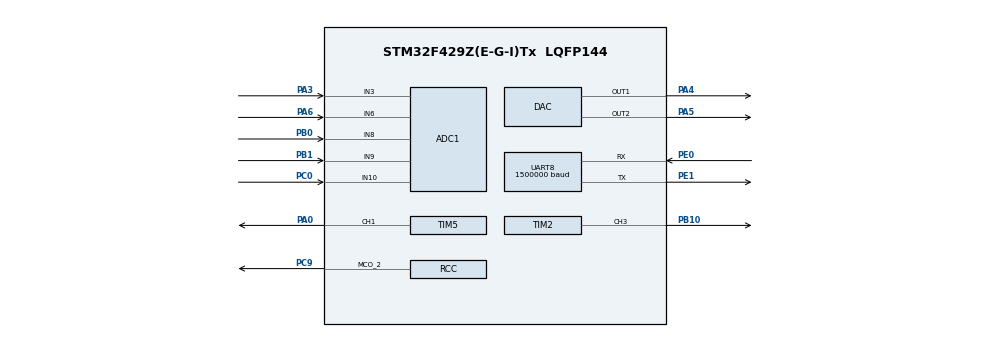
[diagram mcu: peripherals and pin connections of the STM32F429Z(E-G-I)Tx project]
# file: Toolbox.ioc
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ADC1.Channel=ADC_CHANNEL_VREFINT
ADC1.Channel-16\#ChannelRegularConversion=ADC_CHANNEL_TEMPSENSOR
ADC1.Channel-17\#ChannelRegularConversion=ADC_CHANNEL_VREFINT
ADC1.Channel-18\#ChannelRegularConversion=ADC_CHANNEL_VBAT
ADC1.DMAContinuousRequests=ENABLE
ADC1.EOCSelection=EOC_SEQ_CONV
ADC1.ExternalTrigConv=ADC_EXTERNALTRIGCONV_T5_CC1
ADC1.ExternalTrigConvEdge=ADC_EXTERNALTRIGCONVEDGE_RISING
ADC1.NbrOfConversion=3
ADC1.Rank-17\#ChannelRegularConversion=2
ADC1.Rank-18\#ChannelRegularConversion=3
ADC1.SamplingTime-18\#ChannelRegularConversion=ADC_SAMPLETIME_3CYCLES
ADC1.ScanConvMode=ENABLE
ADC1.master=1
Dma.ADC1.2.Channel=DMA_CHANNEL_0
Dma.ADC1.2.Direction=DMA_PERIPH_TO_MEMORY
Dma.ADC1.2.FIFOMode=DMA_FIFOMODE_DISABLE
Dma.ADC1.2.FIFOThreshold=DMA_FIFO_THRESHOLD_HALFFULL
Dma.ADC1.2.Instance=DMA2_Stream0
Dma.ADC1.2.MemBurst=DMA_MBURST_SINGLE
Dma.ADC1.2.MemDataAlignment=DMA_MDATAALIGN_HALFWORD
Dma.ADC1.2.MemInc=DMA_MINC_ENABLE
Dma.ADC1.2.Mode=DMA_CIRCULAR
Dma.ADC1.2.PeriphBurst=DMA_PBURST_SINGLE
Dma.ADC1.2.PeriphDataAlignment=DMA_PDATAALIGN_HALFWORD
Dma.ADC1.2.PeriphInc=DMA_PINC_DISABLE
Dma.ADC1.2.Priority=DMA_PRIORITY_HIGH
Dma.Request0=UART8_TX
Dma.Request1=UART8_RX
Dma.Request2=ADC1
Dma.UART8_RX.1.Channel=DMA_CHANNEL_5
Dma.UART8_RX.1.Direction=DMA_PERIPH_TO_MEMORY
Dma.UART8_RX.1.FIFOMode=DMA_FIFOMODE_DISABLE
Dma.UART8_RX.1.FIFOThreshold=DMA_FIFO_THRESHOLD_HALFFULL
Dma.UART8_RX.1.Instance=DMA1_Stream6
Dma.UART8_RX.1.MemBurst=DMA_MBURST_SINGLE
Dma.UART8_RX.1.MemDataAlignment=DMA_MDATAALIGN_BYTE
Dma.UART8_RX.1.MemInc=DMA_MINC_ENABLE
Dma.UART8_RX.1.Mode=DMA_CIRCULAR
Dma.UART8_RX.1.PeriphBurst=DMA_PBURST_SINGLE
Dma.UART8_RX.1.PeriphDataAlignment=DMA_PDATAALIGN_BYTE
Dma.UART8_RX.1.PeriphInc=DMA_PINC_DISABLE
Dma.UART8_RX.1.Priority=DMA_PRIORITY_VERY_HIGH
Dma.UART8_TX.0.Channel=DMA_CHANNEL_5
Dma.UART8_TX.0.Direction=DMA_MEMORY_TO_PERIPH
Dma.UART8_TX.0.FIFOMode=DMA_FIFOMODE_ENABLE
Dma.UART8_TX.0.FIFOThreshold=DMA_FIFO_THRESHOLD_1QUARTERFULL
Dma.UART8_TX.0.Instance=DMA1_Stream0
Dma.UART8_TX.0.MemBurst=DMA_MBURST_SINGLE
Dma.UART8_TX.0.MemDataAlignment=DMA_MDATAALIGN_BYTE
Dma.UART8_TX.0.MemInc=DMA_MINC_ENABLE
Dma.UART8_TX.0.Mode=DMA_NORMAL
Dma.UART8_TX.0.PeriphBurst=DMA_PBURST_SINGLE
Dma.UART8_TX.0.PeriphDataAlignment=DMA_PDATAALIGN_BYTE
Dma.UART8_TX.0.PeriphInc=DMA_PINC_DISABLE
Dma.UART8_TX.0.Priority=DMA_PRIORITY_VERY_HIGH
Mcu.Family=STM32F4
Mcu.Name=STM32F429Z(E-G-I)Tx
Mcu.Package=LQFP144
NVIC.ADC_IRQn=true\:3\:0\:true
NVIC.DMA1_Stream0_IRQn=true\:1\:0\:true
NVIC.DMA1_Stream6_IRQn=true\:1\:0\:true
NVIC.DMA2_Stream0_IRQn=true\:2\:0\:true
NVIC.PriorityGroup=NVIC_PRIORITYGROUP_4
PA0/WKUP.GPIO_ModeDefaultPP=GPIO_MODE_AF_OD
PA0/WKUP.GPIO_PuPd=GPIO_NOPULL
PA0/WKUP.GPIO_Speed=GPIO_SPEED_LOW
PA0/WKUP.Signal=S_TIM5_CH1
PA1.Signal=ETH_REF_CLK
PA11.Signal=USB_OTG_FS_DM
PA12.Signal=USB_OTG_FS_DP
PA13.Mode=JTAG(5-pin)
PA13.Signal=SYS_JTMS-SWDIO
PA14.Mode=JTAG(5-pin)
PA14.Signal=SYS_JTCK-SWCLK
PA15.Mode=JTAG(5-pin)
PA15.Signal=SYS_JTDI
PA2.Signal=ETH_MDIO
PA3.Signal=ADCx_IN3
PA4.Signal=COMP_DAC1_group
PA5.Signal=COMP_DAC2_group
PA6.Signal=ADCx_IN6
PA7.Signal=ETH_CRS_DV
PA9.Signal=USB_OTG_FS_VBUS
PB0.Signal=ADCx_IN8
PB1.Signal=ADCx_IN9
PB10.GPIO_ModeDefaultPP=GPIO_MODE_AF_PP
PB10.GPIO_PuPd=GPIO_PULLUP
PB10.GPIO_Speed=GPIO_SPEED_HIGH
PB10.Signal=S_TIM2_CH3
PB11.Signal=ETH_TX_EN
PB12.Signal=ETH_TXD0
PB13.Signal=ETH_TXD1
PB3.Mode=JTAG(5-pin)
PB3.Signal=SYS_JTDO-SWO
PB4.Mode=JTAG(5-pin)
PB4.Signal=SYS_JTRST
PC0.Signal=ADCx_IN10
PC1.Signal=ETH_MDC
PC12.Signal=SDIO_CK
PC4.Signal=ETH_RXD0
PC5.Signal=ETH_RXD1
PC8.Signal=SDIO_D0
PC9.GPIO_Mode=GPIO_MODE_AF_PP
PC9.GPIO_PuPd=GPIO_NOPULL
PC9.GPIO_Speed=GPIO_SPEED_HIGH
PC9.Mode=Clock-out-2
PC9.Signal=RCC_MCO_2
PD2.Signal=SDIO_CMD
PE0.GPIO_Mode=GPIO_MODE_AF_PP
PE0.GPIO_PuPd=GPIO_PULLUP
PE0.GPIO_Speed=GPIO_SPEED_HIGH
PE0.Mode=Asynchronous
PE0.Signal=UART8_RX
PE1.GPIO_Mode=GPIO_MODE_AF_PP
PE1.GPIO_PuPd=GPIO_PULLUP
PE1.GPIO_Speed=GPIO_SPEED_HIGH
PE1.Mode=Asynchronous
PE1.Signal=UART8_TX
PH0/OSC_IN.Mode=HSE-External-Oscillator
PH0/OSC_IN.Signal=RCC_OSC_IN
PH1/OSC_OUT.Mode=HSE-External-Oscillator
PH1/OSC_OUT.Signal=RCC_OSC_OUT
ProjectManager.TargetToolchain=TrueSTUDIO 4.3.1
RCC.48MHZClocksFreq_Value=45000000
RCC.AHBFreq_Value=180000000
RCC.APB1CLKDivider=RCC_HCLK_DIV4
RCC.APB1Freq_Value=45000000
RCC.APB1TimFreq_Value=90000000
RCC.APB2CLKDivider=RCC_HCLK_DIV2
RCC.APB2Freq_Value=90000000
RCC.APB2TimFreq_Value=180000000
RCC.CortexFreq_Value=22500000
RCC.HCLKFreq_Value=180000000
RCC.HSE_VALUE=16000000
RCC.HSI_VALUE=16000000
RCC.LSE_VALUE=32768
RCC.PLLI2SN=400
RCC.PLLN=360
RCC.PLLQ=8
RCC.PLLSourceVirtual=RCC_PLLSOURCE_HSE
RCC.RCC_MCO2Source=RCC_MCO2SOURCE_PLLI2SCLK
RCC.RCC_MCODiv2=RCC_MCODIV_4
RCC.SYSCLKFreq_VALUE=180000000
RCC.SYSCLKSource=RCC_SYSCLKSOURCE_PLLCLK
RCC.VCOOutputFreq_Value=360000000
SH.ADCx_IN10.0=ADC1_IN10,IN10
SH.ADCx_IN3.0=ADC1_IN3,IN3
SH.ADCx_IN6.0=ADC1_IN6,IN6
SH.ADCx_IN8.0=ADC1_IN8,IN8
SH.ADCx_IN9.0=ADC1_IN9,IN9
SH.COMP_DAC1_group.0=DAC_OUT1,DAC_OUT1
SH.COMP_DAC2_group.0=DAC_OUT2,DAC_OUT2
SH.S_TIM2_CH3.0=TIM2_CH3,PWM Generation3 CH3
SH.S_TIM5_CH1.0=TIM5_CH1,PWM Generation1 CH1
TIM2.Channel-PWM\ Generation3\ CH3=TIM_CHANNEL_3
TIM2.OCFastMode_PWM-PWM\ Generation3\ CH3=TIM_OCFAST_ENABLE
TIM2.Period=9000
TIM2.Pulse-PWM\ Generation3\ CH3=3000
TIM5.OCFastMode_PWM-PWM\ Generation1\ CH1=TIM_OCFAST_ENABLE
TIM5.Period=180000000
TIM5.Pulse-PWM\ Generation1\ CH1=10
TIM5.TIM_MasterOutputTrigger=TIM_TRGO_OC1REF
UART8.BaudRate=1500000
VP_ADC1_TempSens_Input.Mode=IN-TempSens
VP_ADC1_Vbat_Input.Mode=IN-Vbat
VP_ADC1_Vref_Input.Mode=IN-Vrefint
VP_TIM2_VS_ClockSourceINT.Mode=Internal
VP_TIM5_VS_ClockSourceINT.Mode=Internal

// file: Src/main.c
/**
  ******************************************************************************
  * File Name          : main.c
  * Date               : 05/04/2015 00:15:51
  * Description        : Main program body
  ******************************************************************************
  *
  * COPYRIGHT(c) 2015 STMicroelectronics
  *
  * Redistribution and use in source and binary forms, with or without modification,
  * are permitted provided that the following conditions are met:
  *   1. Redistributions of source code must retain the above copyright notice,
  *      this list of conditions and the following disclaimer.
  *   2. Redistributions in binary form must reproduce the above copyright notice,
  *      this list of conditions and the following disclaimer in the documentation
  *      and/or other materials provided with the distribution.
  *   3. Neither the name of STMicroelectronics nor the names of its contributors
  *      may be used to endorse or promote products derived from this software
  *      without specific prior written permission.
  *
  * THIS SOFTWARE IS PROVIDED BY THE COPYRIGHT HOLDERS AND CONTRIBUTORS "AS IS"
  * AND ANY EXPRESS OR IMPLIED WARRANTIES, INCLUDING, BUT NOT LIMITED TO, THE
  * IMPLIED WARRANTIES OF MERCHANTABILITY AND FITNESS FOR A PARTICULAR PURPOSE ARE
  * DISCLAIMED. IN NO EVENT SHALL THE COPYRIGHT HOLDER OR CONTRIBUTORS BE LIABLE
  * FOR ANY DIRECT, INDIRECT, INCIDENTAL, SPECIAL, EXEMPLARY, OR CONSEQUENTIAL
  * DAMAGES (INCLUDING, BUT NOT LIMITED TO, PROCUREMENT OF SUBSTITUTE GOODS OR
  * SERVICES; LOSS OF USE, DATA, OR PROFITS; OR BUSINESS INTERRUPTION) HOWEVER
  * CAUSED AND ON ANY THEORY OF LIABILITY, WHETHER IN CONTRACT, STRICT LIABILITY,
  * OR TORT (INCLUDING NEGLIGENCE OR OTHERWISE) ARISING IN ANY WAY OUT OF THE USE
  * OF THIS SOFTWARE, EVEN IF ADVISED OF THE POSSIBILITY OF SUCH DAMAGE.
  *
  ******************************************************************************
  */

#include "stm32f4xx_hal.h"

/* USER CODE BEGIN Includes */
#include "ctrl.h"
#include "uart.h"
#include "adc.h"
#include "dac.h"
#include "handles.h"
#include "info.h"
/* USER CODE END Includes */

ADC_HandleTypeDef hadc1;
DMA_HandleTypeDef hdma_adc1;

DAC_HandleTypeDef hdac;

TIM_HandleTypeDef htim2;
TIM_HandleTypeDef htim5;

UART_HandleTypeDef huart8;
DMA_HandleTypeDef hdma_uart8_tx;
DMA_HandleTypeDef hdma_uart8_rx;

/* USER CODE BEGIN PV */
//uint8_t uartBuffer[2][PKG_SIZE];
//uint8_t uartRecv = 0;
/* USER CODE END PV */

void SystemClock_Config(void);
static void MX_GPIO_Init(void);
static void MX_DMA_Init(void);
static void MX_ADC1_Init(void);
static void MX_DAC_Init(void);
static void MX_TIM2_Init(void);
static void MX_TIM5_Init(void);
static void MX_UART8_Init(void);

/* USER CODE BEGIN PFP */
void init(void);
/* USER CODE END PFP */

/* USER CODE BEGIN 0 */
void init(void)
{
	initUART();
	initADC();
	initDAC();
	// PWM Timer
	HAL_TIM_OC_Start(&htim2, TIM_CHANNEL_3);
}

void reset(void)
{
	resetADC();
}
/* USER CODE END 0 */

int main(void)
{

	/* MCU Configuration----------------------------------------------------------*/

	/* Reset of all peripherals, Initializes the Flash interface and the Systick. */
	HAL_Init();

	/* Configure the system clock */
	SystemClock_Config();

	/* Initialize all configured peripherals */
	MX_GPIO_Init();
	MX_DMA_Init();
	MX_ADC1_Init();
	MX_DAC_Init();
	MX_TIM2_Init();
	MX_TIM5_Init();
	MX_UART8_Init();

	/* USER CODE BEGIN 2 */
	init();
	/* USER CODE END 2 */

	/* USER CODE BEGIN 3 */
	for (;;)
		ctrlRootLoop();
	/* USER CODE END 3 */

}

/** System Clock Configuration
*/
void SystemClock_Config(void)
{

	RCC_OscInitTypeDef RCC_OscInitStruct;
	RCC_ClkInitTypeDef RCC_ClkInitStruct;
	RCC_PeriphCLKInitTypeDef PeriphClkInitStruct;

	__PWR_CLK_ENABLE();

	__HAL_PWR_VOLTAGESCALING_CONFIG(PWR_REGULATOR_VOLTAGE_SCALE1);

	RCC_OscInitStruct.OscillatorType = RCC_OSCILLATORTYPE_HSE;
	RCC_OscInitStruct.HSEState = RCC_HSE_ON;
	RCC_OscInitStruct.PLL.PLLState = RCC_PLL_ON;
	RCC_OscInitStruct.PLL.PLLSource = RCC_PLLSOURCE_HSE;
	RCC_OscInitStruct.PLL.PLLM = 8;
	RCC_OscInitStruct.PLL.PLLN = 360;
	RCC_OscInitStruct.PLL.PLLP = RCC_PLLP_DIV2;
	RCC_OscInitStruct.PLL.PLLQ = 8;
	HAL_RCC_OscConfig(&RCC_OscInitStruct);

	HAL_PWREx_ActivateOverDrive();

	RCC_ClkInitStruct.ClockType = RCC_CLOCKTYPE_SYSCLK|RCC_CLOCKTYPE_PCLK1
				      |RCC_CLOCKTYPE_PCLK2;
	RCC_ClkInitStruct.SYSCLKSource = RCC_SYSCLKSOURCE_PLLCLK;
	RCC_ClkInitStruct.AHBCLKDivider = RCC_SYSCLK_DIV1;
	RCC_ClkInitStruct.APB1CLKDivider = RCC_HCLK_DIV4;
	RCC_ClkInitStruct.APB2CLKDivider = RCC_HCLK_DIV2;
	HAL_RCC_ClockConfig(&RCC_ClkInitStruct, FLASH_LATENCY_5);

	PeriphClkInitStruct.PeriphClockSelection = RCC_PERIPHCLK_I2S;
	PeriphClkInitStruct.PLLI2S.PLLI2SN = 400;
	PeriphClkInitStruct.PLLI2S.PLLI2SR = 2;
	HAL_RCCEx_PeriphCLKConfig(&PeriphClkInitStruct);

	HAL_RCC_MCOConfig(RCC_MCO2, RCC_MCO2SOURCE_PLLI2SCLK, RCC_MCODIV_4);

}

/* ADC1 init function */
void MX_ADC1_Init(void)
{

	ADC_ChannelConfTypeDef sConfig;

	/**Configure the global features of the ADC (Clock, Resolution, Data Alignment and number of conversion)
    */
	hadc1.Instance = ADC1;
	hadc1.Init.ClockPrescaler = ADC_CLOCKPRESCALER_PCLK_DIV2;
	hadc1.Init.Resolution = ADC_RESOLUTION12b;
	hadc1.Init.ScanConvMode = ENABLE;
	hadc1.Init.ContinuousConvMode = DISABLE;
	hadc1.Init.DiscontinuousConvMode = DISABLE;
	hadc1.Init.ExternalTrigConvEdge = ADC_EXTERNALTRIGCONVEDGE_RISING;
	hadc1.Init.ExternalTrigConv = ADC_EXTERNALTRIGCONV_T5_CC1;
	hadc1.Init.DataAlign = ADC_DATAALIGN_RIGHT;
	hadc1.Init.NbrOfConversion = 3;
	hadc1.Init.DMAContinuousRequests = ENABLE;
	hadc1.Init.EOCSelection = EOC_SEQ_CONV;
	HAL_ADC_Init(&hadc1);

	/**Configure for the selected ADC regular channel its corresponding rank in the sequencer and its sample time.
    */
	sConfig.Channel = ADC_CHANNEL_VREFINT;
	sConfig.Rank = 3;
	sConfig.SamplingTime = ADC_SAMPLETIME_3CYCLES;
	HAL_ADC_ConfigChannel(&hadc1, &sConfig);

	/**Configure for the selected ADC regular channel its corresponding rank in the sequencer and its sample time.
    */
	sConfig.Rank = 2;
	HAL_ADC_ConfigChannel(&hadc1, &sConfig);

	/**Configure for the selected ADC regular channel its corresponding rank in the sequencer and its sample time.
    */
	sConfig.Channel = ADC_CHANNEL_TEMPSENSOR;
	sConfig.Rank = 1;
	HAL_ADC_ConfigChannel(&hadc1, &sConfig);

}

/* DAC init function */
void MX_DAC_Init(void)
{

	DAC_ChannelConfTypeDef sConfig;

	/**DAC Initialization
    */
	hdac.Instance = DAC;
	HAL_DAC_Init(&hdac);

	/**DAC channel OUT1 config
    */
	sConfig.DAC_Trigger = DAC_TRIGGER_NONE;
	sConfig.DAC_OutputBuffer = DAC_OUTPUTBUFFER_ENABLE;
	HAL_DAC_ConfigChannel(&hdac, &sConfig, DAC_CHANNEL_1);

	/**DAC channel OUT2 config
    */
	HAL_DAC_ConfigChannel(&hdac, &sConfig, DAC_CHANNEL_2);

}

/* TIM2 init function */
void MX_TIM2_Init(void)
{

	TIM_ClockConfigTypeDef sClockSourceConfig;
	TIM_MasterConfigTypeDef sMasterConfig;
	TIM_OC_InitTypeDef sConfigOC;

	htim2.Instance = TIM2;
	htim2.Init.Prescaler = 0;
	htim2.Init.CounterMode = TIM_COUNTERMODE_UP;
	htim2.Init.Period = 9000;
	htim2.Init.ClockDivision = TIM_CLOCKDIVISION_DIV1;
	HAL_TIM_Base_Init(&htim2);

	sClockSourceConfig.ClockSource = TIM_CLOCKSOURCE_INTERNAL;
	HAL_TIM_ConfigClockSource(&htim2, &sClockSourceConfig);

	HAL_TIM_PWM_Init(&htim2);

	sMasterConfig.MasterOutputTrigger = TIM_TRGO_RESET;
	sMasterConfig.MasterSlaveMode = TIM_MASTERSLAVEMODE_DISABLE;
	HAL_TIMEx_MasterConfigSynchronization(&htim2, &sMasterConfig);

	sConfigOC.OCMode = TIM_OCMODE_PWM1;
	sConfigOC.Pulse = 3000;
	sConfigOC.OCPolarity = TIM_OCPOLARITY_HIGH;
	sConfigOC.OCFastMode = TIM_OCFAST_ENABLE;
	HAL_TIM_PWM_ConfigChannel(&htim2, &sConfigOC, TIM_CHANNEL_3);

}

/* TIM5 init function */
void MX_TIM5_Init(void)
{

	TIM_ClockConfigTypeDef sClockSourceConfig;
	TIM_MasterConfigTypeDef sMasterConfig;
	TIM_OC_InitTypeDef sConfigOC;

	htim5.Instance = TIM5;
	htim5.Init.Prescaler = 0;
	htim5.Init.CounterMode = TIM_COUNTERMODE_UP;
	htim5.Init.Period = 180000000;
	htim5.Init.ClockDivision = TIM_CLOCKDIVISION_DIV1;
	HAL_TIM_Base_Init(&htim5);

	sClockSourceConfig.ClockSource = TIM_CLOCKSOURCE_INTERNAL;
	HAL_TIM_ConfigClockSource(&htim5, &sClockSourceConfig);

	HAL_TIM_PWM_Init(&htim5);

	sMasterConfig.MasterOutputTrigger = TIM_TRGO_OC1REF;
	sMasterConfig.MasterSlaveMode = TIM_MASTERSLAVEMODE_DISABLE;
	HAL_TIMEx_MasterConfigSynchronization(&htim5, &sMasterConfig);

	sConfigOC.OCMode = TIM_OCMODE_PWM1;
	sConfigOC.Pulse = 10;
	sConfigOC.OCPolarity = TIM_OCPOLARITY_HIGH;
	sConfigOC.OCFastMode = TIM_OCFAST_ENABLE;
	HAL_TIM_PWM_ConfigChannel(&htim5, &sConfigOC, TIM_CHANNEL_1);

}

/* UART8 init function */
void MX_UART8_Init(void)
{

	huart8.Instance = UART8;
	huart8.Init.BaudRate = 1000000;
	huart8.Init.WordLength = UART_WORDLENGTH_8B;
	huart8.Init.StopBits = UART_STOPBITS_1;
	huart8.Init.Parity = UART_PARITY_NONE;
	huart8.Init.Mode = UART_MODE_TX_RX;
	huart8.Init.HwFlowCtl = UART_HWCONTROL_NONE;
	huart8.Init.OverSampling = UART_OVERSAMPLING_16;
	HAL_UART_Init(&huart8);

}

void MX_DMA_Init(void)
{
	/* DMA controller clock enable */
	__DMA2_CLK_ENABLE();
	__DMA1_CLK_ENABLE();

	/* DMA interrupt init */
	HAL_NVIC_SetPriority(DMA2_Stream0_IRQn, 2, 0);
	HAL_NVIC_EnableIRQ(DMA2_Stream0_IRQn);
	HAL_NVIC_SetPriority(DMA1_Stream6_IRQn, 1, 0);
	HAL_NVIC_EnableIRQ(DMA1_Stream6_IRQn);
	HAL_NVIC_SetPriority(DMA1_Stream0_IRQn, 1, 0);
	HAL_NVIC_EnableIRQ(DMA1_Stream0_IRQn);

}

/** Configure pins as
	* Analog
	* Input
	* Output
	* EVENT_OUT
	* EXTI
     PC1   ------> ETH_MDC
     PA1   ------> ETH_REF_CLK
     PA2   ------> ETH_MDIO
     PA7   ------> ETH_CRS_DV
     PC4   ------> ETH_RXD0
     PC5   ------> ETH_RXD1
     PB11   ------> ETH_TX_EN
     PB12   ------> ETH_TXD0
     PB13   ------> ETH_TXD1
     PC8   ------> SDIO_D0
     PC9   ------> RCC_MCO_2
     PA9   ------> USB_OTG_FS_VBUS
     PA11   ------> USB_OTG_FS_DM
     PA12   ------> USB_OTG_FS_DP
     PC12   ------> SDIO_CK
     PD2   ------> SDIO_CMD
*/
void MX_GPIO_Init(void)
{

	GPIO_InitTypeDef GPIO_InitStruct;

	/* GPIO Ports Clock Enable */
	__GPIOH_CLK_ENABLE();
	__GPIOC_CLK_ENABLE();
	__GPIOA_CLK_ENABLE();
	__GPIOB_CLK_ENABLE();
	__GPIOD_CLK_ENABLE();
	__GPIOE_CLK_ENABLE();

	/*Configure GPIO pins : PC1 PC4 PC5 */
	GPIO_InitStruct.Pin = GPIO_PIN_1|GPIO_PIN_4|GPIO_PIN_5;
	GPIO_InitStruct.Mode = GPIO_MODE_AF_PP;
	GPIO_InitStruct.Pull = GPIO_NOPULL;
	GPIO_InitStruct.Speed = GPIO_SPEED_LOW;
	GPIO_InitStruct.Alternate = GPIO_AF11_ETH;
	HAL_GPIO_Init(GPIOC, &GPIO_InitStruct);

	/*Configure GPIO pins : PA1 PA2 PA7 */
	GPIO_InitStruct.Pin = GPIO_PIN_1|GPIO_PIN_2|GPIO_PIN_7;
	GPIO_InitStruct.Mode = GPIO_MODE_AF_PP;
	GPIO_InitStruct.Pull = GPIO_NOPULL;
	GPIO_InitStruct.Speed = GPIO_SPEED_LOW;
	GPIO_InitStruct.Alternate = GPIO_AF11_ETH;
	HAL_GPIO_Init(GPIOA, &GPIO_InitStruct);

	/*Configure GPIO pins : PB11 PB12 PB13 */
	GPIO_InitStruct.Pin = GPIO_PIN_11|GPIO_PIN_12|GPIO_PIN_13;
	GPIO_InitStruct.Mode = GPIO_MODE_AF_PP;
	GPIO_InitStruct.Pull = GPIO_NOPULL;
	GPIO_InitStruct.Speed = GPIO_SPEED_LOW;
	GPIO_InitStruct.Alternate = GPIO_AF11_ETH;
	HAL_GPIO_Init(GPIOB, &GPIO_InitStruct);

	/*Configure GPIO pins : PC8 PC12 */
	GPIO_InitStruct.Pin = GPIO_PIN_8|GPIO_PIN_12;
	GPIO_InitStruct.Mode = GPIO_MODE_AF_PP;
	GPIO_InitStruct.Pull = GPIO_NOPULL;
	GPIO_InitStruct.Speed = GPIO_SPEED_LOW;
	GPIO_InitStruct.Alternate = GPIO_AF12_SDIO;
	HAL_GPIO_Init(GPIOC, &GPIO_InitStruct);

	/*Configure GPIO pin : PC9 */
	GPIO_InitStruct.Pin = GPIO_PIN_9;
	GPIO_InitStruct.Mode = GPIO_MODE_AF_PP;
	GPIO_InitStruct.Pull = GPIO_NOPULL;
	GPIO_InitStruct.Speed = GPIO_SPEED_HIGH;
	GPIO_InitStruct.Alternate = GPIO_AF0_MCO;
	HAL_GPIO_Init(GPIOC, &GPIO_InitStruct);

	/*Configure GPIO pin : PA9 */
	GPIO_InitStruct.Pin = GPIO_PIN_9;
	GPIO_InitStruct.Mode = GPIO_MODE_INPUT;
	GPIO_InitStruct.Pull = GPIO_NOPULL;
	HAL_GPIO_Init(GPIOA, &GPIO_InitStruct);

	/*Configure GPIO pins : PA11 PA12 */
	GPIO_InitStruct.Pin = GPIO_PIN_11|GPIO_PIN_12;
	GPIO_InitStruct.Mode = GPIO_MODE_AF_PP;
	GPIO_InitStruct.Pull = GPIO_NOPULL;
	GPIO_InitStruct.Speed = GPIO_SPEED_LOW;
	GPIO_InitStruct.Alternate = GPIO_AF10_OTG_FS;
	HAL_GPIO_Init(GPIOA, &GPIO_InitStruct);

	/*Configure GPIO pin : PD2 */
	GPIO_InitStruct.Pin = GPIO_PIN_2;
	GPIO_InitStruct.Mode = GPIO_MODE_AF_PP;
	GPIO_InitStruct.Pull = GPIO_NOPULL;
	GPIO_InitStruct.Speed = GPIO_SPEED_LOW;
	GPIO_InitStruct.Alternate = GPIO_AF12_SDIO;
	HAL_GPIO_Init(GPIOD, &GPIO_InitStruct);

}

/************************ (C) COPYRIGHT STMicroelectronics *****END OF FILE****/
